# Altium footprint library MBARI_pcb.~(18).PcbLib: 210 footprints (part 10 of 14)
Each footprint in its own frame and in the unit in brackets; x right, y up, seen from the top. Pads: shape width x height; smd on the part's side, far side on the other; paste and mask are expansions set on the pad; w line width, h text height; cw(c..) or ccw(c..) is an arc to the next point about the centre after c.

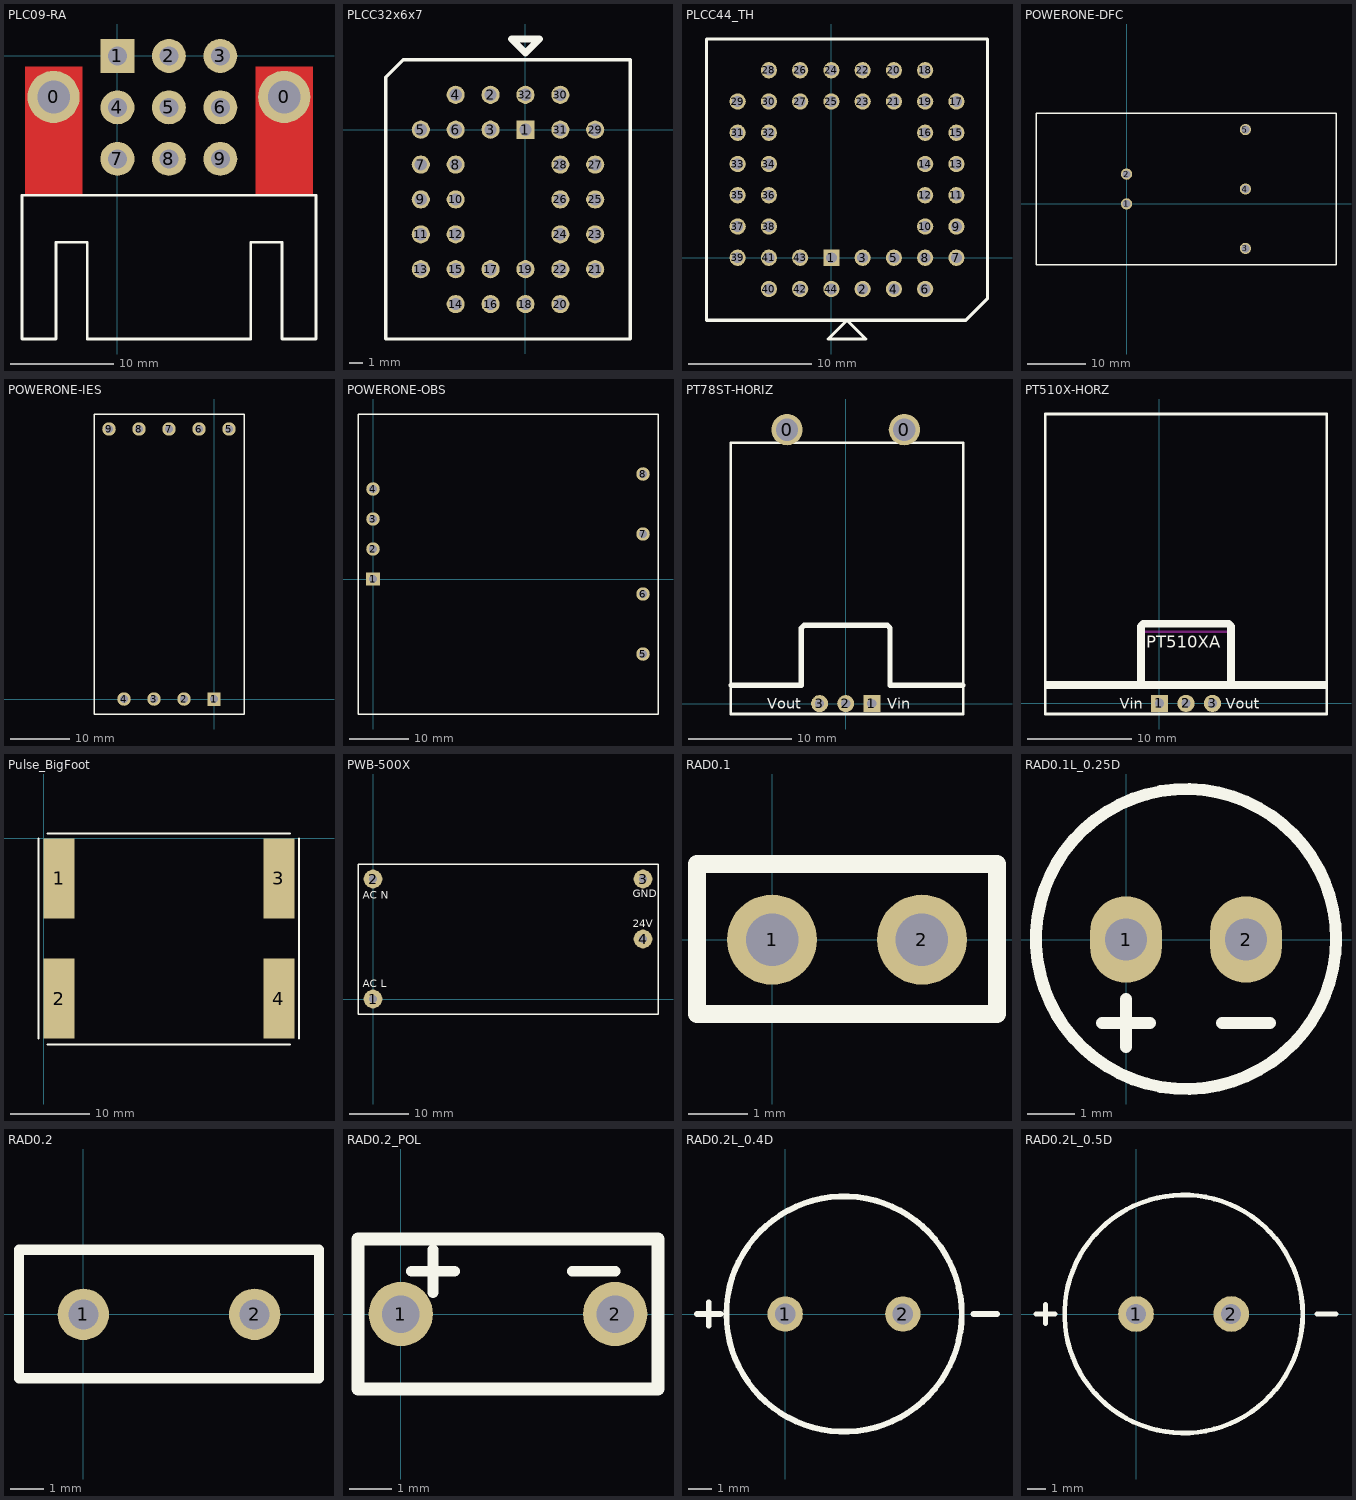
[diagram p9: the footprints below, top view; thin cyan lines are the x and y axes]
## PLC09-RA [mil]
pads (11):
  round 200 hole 125: 0(-244.5,-157) 0(638.5,-157)
  rect 130x130 hole 73: 1(0,0)
  round 130 hole 73: 2(197,0) 3(394,0) 4(0,-197) 5(197,-197) 6(394,-197) 7(0,-394) 8(197,-394) 9(394,-394)
TopLayer:
  rectangle: 528.5,-532 748.5,-40
  rectangle: -354.5,-532 -134.5,-40
TopOverlay:
  lines w10: -365.5,-1084 -235.5,-1084 -235.5,-714 -115.5,-714 -115.5,-1084 510.5,-1084 510.5,-714 630.5,-714 630.5,-1084 760.5,-1084 760.5,-534 -365.5,-534 -365.5,-1084

## PLCC32x6x7 [mil]
pads (32):
  rect 52x52 hole 35: 1(0,0)
  round 52 hole 35: 2(-100,100) 3(-100,0) 4(-200,100) 5(-300,0) 6(-200,0) 7(-300,-100) 8(-200,-100) 9(-300,-200) 10(-200,-200) 11(-300,-300) 12(-200,-300) 13(-300,-400) 14(-200,-500) 15(-200,-400) 16(-100,-500) 17(-100,-400) 18(0,-500) 19(0,-400) 20(100,-500) 21(200,-400) 22(100,-400) 23(200,-300) 24(100,-300) 25(200,-200) 26(100,-200) 27(200,-100) 28(100,-100) 29(200,0) 30(100,100) 31(100,0) 32(0,100)
TopOverlay:
  lines w10: -400,-600 300,-600 300,200 -350,200 -400,150 -400,-600
  lines w20: -40,260 0,220 40,260 -40,260

## PLCC44_TH [mil]
pads (44):
  rect 52x52 hole 35: 1(0,0)
  round 52 hole 35: 2(100,-100) 3(100,0) 4(200,-100) 5(200,0) 6(300,-100) 7(400,0) 8(300,0) 9(400,100) 10(300,100) 11(400,200) 12(300,200) 13(400,300) 14(300,300) 15(400,400) 16(300,400) 17(400,500) 18(300,600) 19(300,500) 20(200,600) 21(200,500) 22(100,600) 23(100,500) 24(0,600) 25(0,500) 26(-100,600) 27(-100,500) 28(-200,600) 29(-300,500) 30(-200,500) 31(-300,400) 32(-200,400) 33(-300,300) 34(-200,300) 35(-300,200) 36(-200,200) 37(-300,100) 38(-200,100) 39(-300,0) 40(-200,-100) 41(-200,0) 42(-100,-100) 43(-100,0) 44(0,-100)
TopOverlay:
  lines w10: -400,-200 430,-200 500,-130 500,700 -350,700 -400,700 -400,650 -400,-200 ; -10,-260 100,-260 110,-260 50,-200 -10,-260

## POWERONE-DFC [mil] "PowerOne DC->DC Converter"
height 420
pads (5):
  round 76 hole 52: 1(0,0) 2(0,200) 3(800,-300) 4(800,100) 5(800,500)
TopOverlay:
  lines w10: -610,-410 -610,610 1410,610 1410,-410 -610,-410

## POWERONE-IES [mil]
pads (9):
  rect 90x90 hole 52: 1(0,0)
  round 90 hole 52: 2(-200,0) 3(-400,0) 4(-600,0) 5(100,1800) 6(-100,1800) 7(-300,1800) 8(-500,1800) 9(-700,1800)
TopOverlay:
  lines w10: -800,-100 -800,1900 200,1900 200,-100 -800,-100

## POWERONE-OBS [mil]
pads (8):
  rect 90x90 hole 52: 1(0,0)
  round 90 hole 52: 2(0,200) 3(0,400) 4(0,600) 5(1800,-500) 6(1800,-100) 7(1800,300) 8(1800,700)
TopOverlay:
  lines w10: -100,-900 1900,-900 1900,1100 -100,1100 -100,-900

## PT78ST-HORIZ [mil]
pads (5):
  round 120 hole 86: 0(-225,1050) 0(225,1050)
  rect 65x65 hole 35: 1(100,0)
  round 65 hole 35: 2(0,0) 3(-100,0)
TopOverlay:
  lines w10: -440,-40 -440,1000 450,1000 450,-40 -150,-40 -440,-40
  lines w20: -440,70 -170,70 -170,290 -160,300 160,300 170,290 170,70 450,70
  text "Vin" at 160,-20 h40
  text "Vout" at -300,-20 h40

## PT510X-HORZ [mil]
pads (3):
  rect 65x65 hole 35: 1(0,0)
  round 65 hole 35: 2(100,0) 3(200,0)
TopOverlay:
  lines w10: -430,-40 -430,1090 630,1090 630,-40 -50,-40 -430,-40
  lines w30: -420,70 620,70 ; -70,70 -70,290 -60,300 260,300 270,290 270,70
  text "PT510XA" at -50,210 h45
  text "Vin" at -150,-20 h40
  text "Vout" at 250,-20 h40
KeepOutLayer:
  lines w10: -70,70 -70,270 270,270 270,70 -70,70

## Pulse_BigFoot [mil] "Pulse engineering big foot footprint"
pads (4):
  rect 155x400 smd: 1(77.5,-200) 2(77.5,-800) 3(1174.5,-200) 4(1174.5,-800)
TopOverlay:
  lines w10: -25,-1000 -25,0 ; 20,-1030 1230,-1030 ; 20,25 1230,25 ; 1275,-1000 1275,0

## PWB-500X [mil]
pads (4):
  round 125 hole 52: 1(0,0) 2(0,800) 3(1800,800) 4(1800,400)
TopOverlay:
  lines w10: -100,-100 1900,-100 1900,900 -100,900 -100,-100
  text "GND" at 1730,680 h50
  text "AC N" at -70,670 h50
  text "24V" at 1730,480 h50
  text "AC L" at -70,80 h50

## RAD0.1 [mil]
pads (2):
  round 60 hole 35: 1(0,0) 2(100,0)
TopOverlay:
  lines w12: -50,-49.51 -50,50.49 150,50.49 150,-49.51 -50,-49.51

## RAD0.1L_0.25D [mil]
pads (2):
  oval 60x72 hole 35: 1(0,0) 2(100,0)
TopOverlay:
  circle w10: c50,0.45 r125
  lines w10: -20,-69.55 20,-69.55 ; 0,-89.55 0,-49.55 ; 80,-69.55 120,-69.55

## RAD0.2 [mil]
pads (2):
  round 60 hole 35: 1(0,0) 2(200,0)
TopOverlay:
  lines w12: -75,-74.59 -75,75.41 275,75.41 275,-74.59 -75,-74.59

## RAD0.2_POL [mil] "Polarized Cap"
pads (2):
  round 60 hole 35: 1(0,0) 2(200,0)
TopOverlay:
  lines w10: 10,40 50,40 ; 30,20 30,60 ; 160,40 200,40
  lines w12: -40,-70 240,-70 240,70 -40,70 -40,-70

## RAD0.2L_0.4D [mil]
pads (2):
  round 60 hole 35: 1(0,0) 2(200,0)
TopOverlay:
  circle w10: c100,0 r200
  lines w10: -150,0 -110,0 ; -130,-20 -130,20 ; 320,0 360,0

## RAD0.2L_0.5D [mil]
pads (2):
  round 75 hole 42: 1(0,0) 2(200,0)
TopOverlay:
  circle w10: c100,0 r250
  lines w10: -210,0 -170,0 ; -190,-20 -190,20 ; 380,0 420,0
